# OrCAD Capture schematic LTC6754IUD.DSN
size A

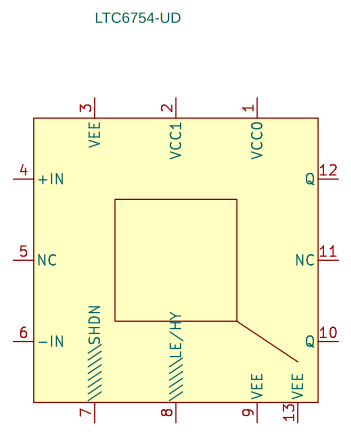
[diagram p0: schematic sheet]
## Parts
U1  LTC6754-UD  [LTC-UD-12-1855]

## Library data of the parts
U1 = LTC6754-UD: IC,HIGH SPEED RAIL-TO-RAIL, INPUT COMPARATOR WITH LVDS COMPATIBLE OUTPUTS; CLASS: IC; Manufacturer: LINEAR TECH.; Manufacturer PN: LTC6754IUD#PBF; PART_NUMBER: LTC6754IUD#PBF; Package Type: ??

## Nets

Not connected (* = marked no-connect by the designer): U1 1(VCC0) 2(VCC1) 3(VEE) 4(+IN) 5(NC) 6(-IN) 7(\\\\\\\\SHDN) 8(\\\\\\LE/HY) 9(VEE) 10(Q) 11(NC) 12(Q) 13(VEE)
